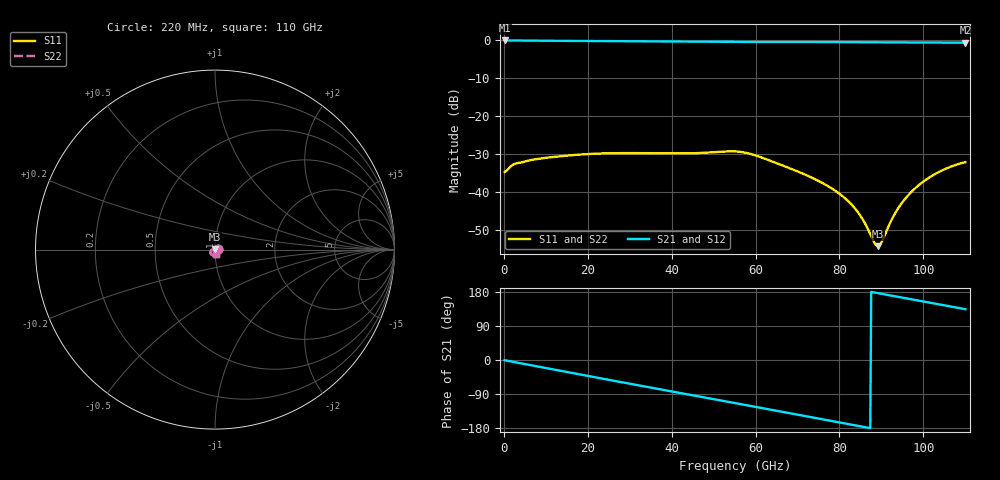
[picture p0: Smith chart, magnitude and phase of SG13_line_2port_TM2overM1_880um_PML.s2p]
#  Hz  S  RI  R  50
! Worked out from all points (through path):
!   500 points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, 220 MHz to 110 GHz, reference 50 ohm
!   highest |S21| = -0.15 dB at 220 MHz (marker M1); lowest = -0.7 dB at 110 GHz (marker M2)
!   group delay of S21, straight-line fit = 5.69 ps
!   lowest |S11| = -54.4 dB at 89.1 GHz (marker M3), VSWR 1.00, Z = 50.1 + j0.179 ohm
!   |S11| at or under -10 dB: start of sweep to end of sweep
!   |S22| runs from -54.4 to -29.4 dB; largest |S21 - S12| = 4.6e-07
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2.2e8  0.0181 0.000682  0.9823 -0.00871  0.9823 -0.00871  0.0181 0.000682
2.42e9  0.0229 0.00224  0.9743 -0.0898  0.9743 -0.0898  0.0229 0.00224
6.16e9  0.0258 -0.00135  0.9501 -0.2215  0.9501 -0.2215  0.0258 -0.00135
1.276e10  0.0273 -0.00985  0.8657 -0.4393  0.8657 -0.4393  0.0273 -0.00985
1.87e10  0.0253 -0.0179  0.7486 -0.6115  0.7486 -0.6115  0.0253 -0.0179
2.794e10  0.0163 -0.0277  0.5046 -0.8183  0.5046 -0.8183  0.0163 -0.0277
3.696e10  0.00515 -0.0316  0.2157 -0.9309  0.2157 -0.9309  0.00515 -0.0316
4.576e10  -0.00522 -0.0317  -0.0841 -0.9444  -0.0841 -0.9444  -0.00522 -0.0317
5.522e10  -0.0205 -0.027  -0.3843 -0.8561  -0.3843 -0.8561  -0.0205 -0.027
6.402e10  -0.0232 -0.00909  -0.6277 -0.6996  -0.6277 -0.6996  -0.0232 -0.00909
7.348e10  -0.0152 -8.44e-05  -0.8234 -0.4494  -0.8234 -0.4494  -0.0152 -8.45e-05
7.876e10  -0.0103 0.00219  -0.8915 -0.286  -0.8915 -0.286  -0.0103 0.00219
8.272e10  -0.00627 0.0029  -0.9215 -0.1567  -0.9215 -0.1567  -0.00627 0.0029
8.514e10  -0.0037 0.00285  -0.9306 -0.0763  -0.9306 -0.0763  -0.0037 0.00285
8.822e10  -0.000309 0.00215  -0.9319 0.0267  -0.9319 0.0267  -0.000309 0.00215
8.91e10  0.000664 0.00179  -0.9302 0.0563  -0.9302 0.0563  0.000664 0.00179
8.998e10  0.00164 0.00136  -0.9274 0.0857  -0.9274 0.0857  0.00164 0.00136
9.174e10  0.00354 0.000238  -0.9192 0.1436  -0.9192 0.1436  0.00354 0.000238
9.482e10  0.00657 -0.00254  -0.8957 0.2435  -0.8957 0.2435  0.00657 -0.00254
9.878e10  0.0093 -0.00763  -0.8498 0.3661  -0.8498 0.3661  0.0093 -0.00763
1.0428e11  0.00933 -0.0164  -0.7588 0.5209  -0.7588 0.5209  0.00933 -0.0164
1.1e11  0.00363 -0.0241  -0.6382 0.6598  -0.6382 0.6598  0.00363 -0.0241
